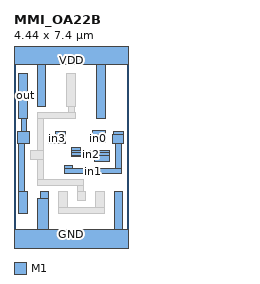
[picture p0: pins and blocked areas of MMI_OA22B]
MACRO MMI_OA22B
	CLASS CORE ;
	FOREIGN MMI_OA22B 0 0 ;
	SIZE 4.44 BY 7.4 ;
	SYMMETRY X Y ;
	SITE CORE1 ;
	PIN out
		DIRECTION output ;
		USE SIGNAL ;
		PORT
			LAYER M1 ;
			RECT 0.18 4.81 0.52 6.57 ;
			LAYER M1 ;
			RECT 0.275 4.295 0.505 4.81 ;
			LAYER M1 ;
			RECT 0.145 3.845 0.595 4.295 ;
			LAYER M1 ;
			RECT 0.18 1.96 0.41 3.845 ;
			LAYER M1 ;
			RECT 0.18 1.12 0.52 1.96 ;
		END
		AntennaDiffArea 1.3248 ;
	END out
	PIN in1
		DIRECTION input ;
		USE SIGNAL ;
		PORT
			LAYER M1 ;
			RECT 3.89 4.195 4.265 4.305 ;
			LAYER M1 ;
			RECT 3.855 3.855 4.265 4.195 ;
			LAYER M1 ;
			RECT 1.955 2.88 2.295 2.99 ;
			LAYER M1 ;
			RECT 3.96 2.88 4.19 3.855 ;
			LAYER M1 ;
			RECT 1.955 2.65 4.19 2.88 ;
		END
		AntennaGateArea 0.4968 ;
	END in1
	PIN GND
		DIRECTION inout ;
		USE GROUND ;
		PORT
			LAYER M1 ;
			RECT 1.02 1.695 1.36 1.96 ;
			LAYER M1 ;
			RECT 0.9 0.5 1.36 1.695 ;
			LAYER M1 ;
			RECT 3.9 0.5 4.24 1.96 ;
			LAYER M1 ;
			RECT 0 -0.5 4.44 0.5 ;
		END
	END GND
	PIN in2
		DIRECTION input ;
		USE SIGNAL ;
		PORT
			LAYER M1 ;
			RECT 2.255 3.58 2.595 3.67 ;
			LAYER M1 ;
			RECT 2.255 3.47 3.71 3.58 ;
			LAYER M1 ;
			RECT 2.255 3.35 3.715 3.47 ;
			LAYER M1 ;
			RECT 2.255 3.33 2.595 3.35 ;
			LAYER M1 ;
			RECT 3.12 3.13 3.715 3.35 ;
		END
		AntennaGateArea 0.4968 ;
	END in2
	PIN VDD
		DIRECTION inout ;
		USE POWER ;
		PORT
			LAYER M1 ;
			RECT 0 6.9 4.44 7.9 ;
			LAYER M1 ;
			RECT 0.9 5.29 1.24 6.9 ;
			LAYER M1 ;
			RECT 3.205 4.81 3.545 6.9 ;
		END
	END VDD
	PIN in3
		DIRECTION input ;
		USE SIGNAL ;
		PORT
			LAYER M1 ;
			RECT 1.625 4.19 2.015 4.295 ;
			LAYER M1 ;
			RECT 1.36 3.85 2.015 4.19 ;
			LAYER M1 ;
			RECT 1.625 3.845 2.015 3.85 ;
		END
		AntennaGateArea 0.4968 ;
	END in3
	PIN in0
		DIRECTION input ;
		USE SIGNAL ;
		PORT
			LAYER M1 ;
			RECT 3.07 4.2 3.55 4.36 ;
			LAYER M1 ;
			RECT 2.985 3.86 3.55 4.2 ;
		END
		AntennaGateArea 0.4968 ;
	END in0
	OBS
		LAYER M1 ;
		RECT 2.05 5.29 2.39 6.57 ;
		LAYER M1 ;
		RECT 2.12 5.04 2.35 5.29 ;
		LAYER M1 ;
		RECT 0.9 4.81 2.395 5.04 ;
		LAYER M1 ;
		RECT 0.9 3.55 1.13 4.81 ;
		LAYER M1 ;
		RECT 0.64 3.21 1.13 3.55 ;
		LAYER M1 ;
		RECT 0.9 2.42 1.13 3.21 ;
		LAYER M1 ;
		RECT 0.9 2.19 2.69 2.42 ;
		LAYER M1 ;
		RECT 2.46 1.96 2.69 2.19 ;
		LAYER M1 ;
		RECT 1.74 1.35 2.08 1.96 ;
		LAYER M1 ;
		RECT 2.46 1.62 2.8 1.96 ;
		LAYER M1 ;
		RECT 3.18 1.35 3.52 1.96 ;
		LAYER M1 ;
		RECT 1.74 1.12 3.52 1.35 ;
	END
END MMI_OA22B
